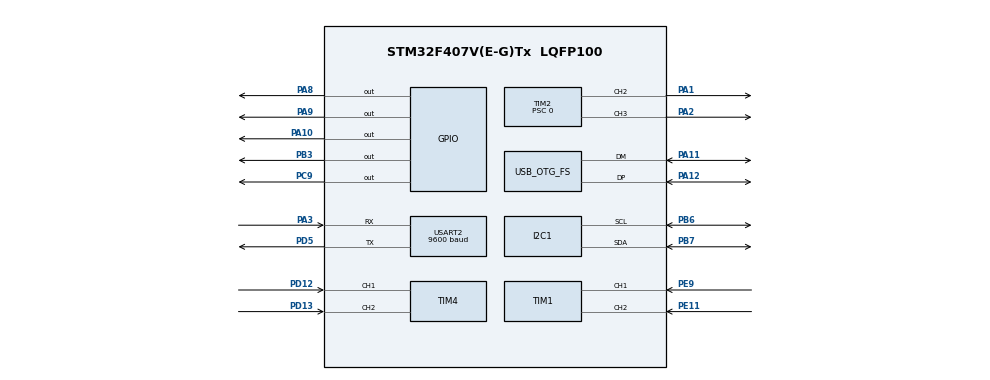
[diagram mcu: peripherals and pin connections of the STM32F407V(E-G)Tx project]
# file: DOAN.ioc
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I2C1.I2C_Mode=I2C_Fast
Mcu.Family=STM32F4
Mcu.Name=STM32F407V(E-G)Tx
Mcu.Package=LQFP100
NVIC.OTG_FS_IRQn=true\:5\:0\:true\:false\:true\:false\:true\:true
NVIC.PriorityGroup=NVIC_PRIORITYGROUP_4
NVIC.TIM3_IRQn=true\:0\:0\:true\:false\:true\:true\:true\:true
NVIC.USART2_IRQn=true\:0\:0\:false\:false\:true\:true\:true\:true
PA1.Signal=S_TIM2_CH2
PA10.Signal=GPIO_Output
PA11.Mode=Device_Only
PA11.Signal=USB_OTG_FS_DM
PA12.Mode=Device_Only
PA12.Signal=USB_OTG_FS_DP
PA13.Mode=Serial_Wire
PA13.Signal=SYS_JTMS-SWDIO
PA14.Mode=Serial_Wire
PA14.Signal=SYS_JTCK-SWCLK
PA2.Signal=S_TIM2_CH3
PA3.Mode=Asynchronous
PA3.Signal=USART2_RX
PA8.Signal=GPIO_Output
PA9.Signal=GPIO_Output
PB3.Signal=GPIO_Output
PB6.Mode=I2C
PB6.Signal=I2C1_SCL
PB7.Mode=I2C
PB7.Signal=I2C1_SDA
PC9.Signal=GPIO_Output
PD12.GPIO_PuPd=GPIO_PULLUP
PD12.Signal=S_TIM4_CH1
PD13.GPIO_PuPd=GPIO_PULLUP
PD13.Signal=S_TIM4_CH2
PD5.Mode=Asynchronous
PD5.Signal=USART2_TX
PE11.GPIO_PuPd=GPIO_PULLUP
PE11.Signal=S_TIM1_CH2
PE9.GPIO_PuPd=GPIO_PULLUP
PE9.Signal=S_TIM1_CH1
PH0-OSC_IN.Mode=HSE-External-Oscillator
PH0-OSC_IN.Signal=RCC_OSC_IN
PH1-OSC_OUT.Mode=HSE-External-Oscillator
PH1-OSC_OUT.Signal=RCC_OSC_OUT
ProjectManager.HeapSize=0x200
ProjectManager.StackSize=0x400
ProjectManager.TargetToolchain=STM32CubeIDE
RCC.48MHZClocksFreq_Value=48000000
RCC.AHBFreq_Value=168000000
RCC.APB1CLKDivider=RCC_HCLK_DIV4
RCC.APB1Freq_Value=42000000
RCC.APB1TimFreq_Value=84000000
RCC.APB2CLKDivider=RCC_HCLK_DIV4
RCC.APB2Freq_Value=42000000
RCC.APB2TimFreq_Value=84000000
RCC.CortexFreq_Value=168000000
RCC.HCLKFreq_Value=168000000
RCC.HSE_VALUE=25000000
RCC.HSI_VALUE=16000000
RCC.LSE_VALUE=32768
RCC.PLLM=25
RCC.PLLN=336
RCC.PLLQ=7
RCC.SYSCLKFreq_VALUE=168000000
RCC.SYSCLKSource=RCC_SYSCLKSOURCE_PLLCLK
RCC.VCOOutputFreq_Value=336000000
SH.S_TIM1_CH1.0=TIM1_CH1,Encoder_Interface
SH.S_TIM1_CH2.0=TIM1_CH2,Encoder_Interface
SH.S_TIM2_CH2.0=TIM2_CH2,PWM Generation2 CH2
SH.S_TIM2_CH3.0=TIM2_CH3,PWM Generation3 CH3
SH.S_TIM4_CH1.0=TIM4_CH1,Encoder_Interface
SH.S_TIM4_CH2.0=TIM4_CH2,Encoder_Interface
TIM1.EncoderMode=TIM_ENCODERMODE_TI12
TIM1.IC1Polarity=TIM_ICPOLARITY_FALLING
TIM1.IC2Filter=0
TIM1.IC2Polarity=TIM_ICPOLARITY_FALLING
TIM2.AutoReloadPreload=TIM_AUTORELOAD_PRELOAD_ENABLE
TIM2.Channel-PWM\ Generation2\ CH2=TIM_CHANNEL_2
TIM2.Channel-PWM\ Generation3\ CH3=TIM_CHANNEL_3
TIM2.Period=4199
TIM2.Prescaler=0
TIM3.AutoReloadPreload=TIM_AUTORELOAD_PRELOAD_ENABLE
TIM3.Period=99
TIM3.Prescaler=8399
TIM4.EncoderMode=TIM_ENCODERMODE_TI12
TIM4.IC1Polarity=TIM_ICPOLARITY_FALLING
TIM4.IC2Filter=0
TIM4.IC2Polarity=TIM_ICPOLARITY_FALLING
USART2.BaudRate=9600
USART2.VirtualMode=VM_ASYNC
USB_DEVICE.CLASS_NAME_FS=CDC
USB_DEVICE.VirtualMode-CDC_FS=Cdc
USB_DEVICE.VirtualModeFS=Cdc_FS
USB_OTG_FS.VirtualMode=Device_Only
VP_TIM2_VS_ClockSourceINT.Mode=Internal
VP_TIM3_VS_ClockSourceINT.Mode=Internal
VP_USB_DEVICE_VS_USB_DEVICE_CDC_FS.Mode=CDC_FS
board=custom

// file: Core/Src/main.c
/* USER CODE BEGIN Header */
/**
  ******************************************************************************
  * @file           : main.c
  * @brief          : Main program body - Robot Balancing (Single Loop)
  ******************************************************************************
  */
/* USER CODE END Header */
#include "main.h"
#include "usb_device.h"

/* USER CODE BEGIN Includes */
#include <stdio.h>
#include <stdlib.h>
#include <math.h>
#include "string.h"
#include "usbd_cdc_if.h"
#include "mpu6050.h"
#include "pid.h"
#include "PID_motor.h"
#include "state_machine.h"
/* USER CODE END Includes */

/* USER CODE BEGIN PTD */
typedef enum {
    ROBOT_OFF,
    ROBOT_RUNNING
} RobotState_t;
/* USER CODE END PTD */

I2C_HandleTypeDef hi2c1;

TIM_HandleTypeDef htim1;
TIM_HandleTypeDef htim2;
TIM_HandleTypeDef htim3;
TIM_HandleTypeDef htim4;

UART_HandleTypeDef huart2;

/* USER CODE BEGIN PV */

gyro_data gyro;
accel_data accel;
filtered_angle_t angle = {0, 0};

volatile float Angle_Pitch = 0.0f;
volatile float Angle_Roll = 0.0f;
volatile float Gyro_X_Rate = 0.0f;
volatile float Gyro_Y_Rate = 0.0f;

//float Kp_ang = 60.0f;
//float Ki_ang = 0.015f;
//float Kd_ang = 1.45f;

float Kp_ang = 60.0f;
float Ki_ang = 0.005f;
float Kd_ang = 1.2;

float Kp_spd = 5.0f;
float Ki_spd = 0.005f;

float Setpoint_Angle = 8.0f;
volatile uint32_t cnt = 0;

// --- THÔNG SỐ CẤU HÌNH ---
        float Base_Angle = 8.0f;   // Góc cân bằng chuẩn (Đứng yên)
        float Tilt_Step  = 5.5f;   // Độ nghiêng để chạy tới
        float Ramp_Step  = 0.05f;  // Độ mượt chuyển đổi (tăng số này nếu muốn chuyển trạng thái nhanh hơn)

float Error_Ang = 0.0f;
float Prev_Error_Ang = 0.0f;
float I_Part_Ang = 0.0f;
float Target_Speed = 0.0f;

float v_filter = 0.0f;
float Encoder_Speed = 0.0f;
float Error_Spd = 0.0f;
float I_Part_Spd = 0.0f;
float PWM_Out = 0.0f;

volatile uint8_t timer_flag = 0;
const float dt = 0.01f;

int flag1, flag2, flag3 = 0;

uint8_t TxBuffer1[] = "I2C done!\r\n";
uint8_t TxBufferLen1 = sizeof(TxBuffer1);

uint8_t TxBuffer2[] = "Encoder done!\r\n";
uint8_t TxBufferLen2 = sizeof(TxBuffer2);

uint8_t TxBuffer3[] = "PWM done!\r\n";
uint8_t TxBufferLen3 = sizeof(TxBuffer3);
//char usb_buffer[64];

 int16_t enc1_new = 0;
 int16_t enc2_new = 0;
int16_t enc1_old = 0;
int16_t enc2_old = 0;

volatile uint8_t send_usb_flag = 0;
static uint16_t time_counter = 0;

//Gửi bluetooth
uint8_t rxData;

/* USER CODE END PV */

void SystemClock_Config(void);
static void MX_GPIO_Init(void);
static void MX_I2C1_Init(void);
static void MX_TIM2_Init(void);
static void MX_TIM3_Init(void);
static void MX_TIM1_Init(void);
static void MX_TIM4_Init(void);
static void MX_USART2_UART_Init(void);

/* USER CODE BEGIN 0 */
// Các biến hỗ trợ đọc encoder trong ngắt
//volatile uint8_t A_state = 0, B_state = 0;
//volatile uint8_t A2_state = 0, B2_state = 0;

/*
void HAL_GPIO_EXTI_Callback(uint16_t GPIO_Pin)
{
    if (GPIO_Pin == GPIO_PIN_0) // Encoder 1
    {
        A_state = HAL_GPIO_ReadPin(GPIOC, GPIO_PIN_0);
        B_state = HAL_GPIO_ReadPin(GPIOB, GPIO_PIN_0);
        if (A_state != B_state) encoder_value--;
        else encoder_value++;
    }
    else if (GPIO_Pin == GPIO_PIN_1) // Encoder 2
    {
        A2_state = HAL_GPIO_ReadPin(GPIOC, GPIO_PIN_1);
        B2_state = HAL_GPIO_ReadPin(GPIOB, GPIO_PIN_1);
        if (A2_state != B2_state) encoder2_value--;
        else encoder2_value++;
    }
}
*/

/* ===============================================================
 * HÀM ĐIỀU KHIỂN MOTOR
 * =============================================================== */
void Motor_Control(float pwm_input)
{
    if (pwm_input > 4199.0f) pwm_input = 4199.0f;
    else if (pwm_input < -4199.0f) pwm_input = -4199.0f;

    int pwm_val = (int)fabs(pwm_input);

    if (pwm_input > 0) // Forward
    {
        HAL_GPIO_WritePin(GPIOA, GPIO_PIN_10, 1);
        HAL_GPIO_WritePin(GPIOA, GPIO_PIN_9, 0);

        HAL_GPIO_WritePin(GPIOA, GPIO_PIN_8, 1);
        HAL_GPIO_WritePin(GPIOC, GPIO_PIN_9, 0);
    }
    else if (pwm_input < 0) // Backward
    {
        HAL_GPIO_WritePin(GPIOA, GPIO_PIN_10, 0); //AIN2
        HAL_GPIO_WritePin(GPIOA, GPIO_PIN_9, 1); //AIN1

        HAL_GPIO_WritePin(GPIOA, GPIO_PIN_8, 0); //BIN1
        HAL_GPIO_WritePin(GPIOC, GPIO_PIN_9, 1); //BIN2
    }
    else // Stop
    {
        pwm_val = 0;
    }

    __HAL_TIM_SET_COMPARE(&htim2, TIM_CHANNEL_2, pwm_val);
    __HAL_TIM_SET_COMPARE(&htim2, TIM_CHANNEL_3, pwm_val);
}

/*
#define ADD 0xD0
#define RTD 57.2957

int16_t ax = 0, ay = 0, az = 0, gx = 0, gy = 0, gz = 0;
float AX, AY, AZ, GX, GY, GZ;
float pitch = 0, roll = 0, prev_pitch = 0;
float filtered_pitch = 0;

void MPU6050Init(void)
{
	uint8_t check;
	uint8_t mData;
	HAL_I2C_Mem_Read(&hi2c1, ADD, 0x75, 1, &check, 1, 1000);
	if(check == 0x68)
	{
		mData = 0x00;
		HAL_I2C_Mem_Write(&hi2c1, ADD, 0x6B, 1, &mData, 1, 1000);
		mData = 0x07;
		HAL_I2C_Mem_Write(&hi2c1, ADD, 0x19, 1, &mData, 1, 1000);
		mData = 0x00;
		HAL_I2C_Mem_Write(&hi2c1, ADD, 0x1B, 1, &mData, 1, 1000);
		mData = 0x00;
		HAL_I2C_Mem_Write(&hi2c1, ADD, 0x1C, 1, &mData, 1, 1000);
	}
}

void MPU6050ReadG(void)
{
	uint8_t dataG[6];
	HAL_I2C_Mem_Read(&hi2c1, ADD, 0x43, 1, dataG, 6, 1000);
	gx = (int16_t) (dataG[0] << 8 | dataG[1]);
	gy = (int16_t) (dataG[2] << 8 | dataG[3]);
	gz = (int16_t) (dataG[4] << 8 | dataG[5]);
	GX =(float) gx / 131.0;
	GY =(float) gy / 131.0;
	GZ =(float) gz / 131.0;

}

void MPU6050ReadA(void)
{
	uint8_t dataA[6];
	HAL_I2C_Mem_Read(&hi2c1, ADD, 0x3B, 1, dataA, 6, 1000);
	ax = (int16_t) (dataA[0] << 8 | dataA[1]);
	ay = (int16_t) (dataA[2] << 8 | dataA[3]);
	az = (int16_t) (dataA[4] << 8 | dataA[5]);
	AX = (float) ax / 16384.0;
	AY = (float) ay / 16384.0;
	AZ = (float) az / 16384.0;

}

void MPU6050_getAngle(float AX, float AY, float AZ, float GX, float GY, float GZ)
{
	float pitchG = pitch + GX * (10000 / 1000000.0f);
	float rollG = roll + GY * (10000 / 1000000.0f);

	float pitchA = atan2(AY, sqrt(AX * AX + AZ * AZ)) * RTD;
	float rollA = atan2(AX, sqrt(AY * AY + AZ * AZ)) * RTD;

	pitch = 0.98 * pitchG + 0.02 * pitchA;
	roll = 0.98 * rollG + 0.02 * rollA;
}

void MPU6050_filter(float pitch, float GX, float dt)
{
	filtered_pitch = 0.98f * (prev_pitch + GX * dt) + 0.02 * pitch;
	prev_pitch = filtered_pitch;
}
*/

/* USER CODE END 0 */

int main(void)
{

  /* MCU Configuration--------------------------------------------------------*/

  /* Reset of all peripherals, Initializes the Flash interface and the Systick. */
  HAL_Init();

  /* Configure the system clock */
  SystemClock_Config();

  /* Initialize all configured peripherals */
  MX_GPIO_Init();
  MX_I2C1_Init();
  MX_TIM2_Init();
  MX_TIM3_Init();
  MX_USB_DEVICE_Init();
  MX_TIM1_Init();
  MX_TIM4_Init();
  MX_USART2_UART_Init();
  /* USER CODE BEGIN 2 */
  HAL_NVIC_SetPriority(SysTick_IRQn, 0, 0);
  //HAL_NVIC_SetPriority(OTG_FS_IRQn, 5, 0);7-
  mpu6050_init();
  //MPU6050Init();

  // 3. Enable Motor Driver
  HAL_GPIO_WritePin(GPIOB, GPIO_PIN_3, GPIO_PIN_SET);

  // 4. Start Timer
  HAL_TIM_Base_Start_IT(&htim3);
  HAL_TIM_PWM_Start(&htim2, TIM_CHANNEL_2);
  HAL_TIM_PWM_Start(&htim2, TIM_CHANNEL_3);

  HAL_TIM_Encoder_Start(&htim1, TIM_CHANNEL_ALL);
  HAL_TIM_Encoder_Start(&htim4, TIM_CHANNEL_ALL);

  //HAL_UART_Receive_IT(&huart2,&rxData,1);
  /* USER CODE END 2 */

  /* Infinite loop */
  /* USER CODE BEGIN WHILE */
  while (1)
  {
	  /*
	  if(send_usb_flag == 1)
	  {
		  send_usb_flag = 0;
		  int len = sprintf(usb_buffer, "%.2f,%.2f,%.2f\r\n", Angle_Pitch, 1000.0f, v_filter);
		  int len = sprintf(usb_buffer, "%d,%d,%.0f,%.0f,%.0f\r\n", enc1_new, enc2_new, Angle_Pitch, PWM_Out, Encoder_Speed);
		  CDC_Transmit_FS((uint8_t*)usb_buffer, len);
	  }
	  */

    /* USER CODE END WHILE */

  }
}

void SystemClock_Config(void)
{
  RCC_OscInitTypeDef RCC_OscInitStruct = {0};
  RCC_ClkInitTypeDef RCC_ClkInitStruct = {0};

  /** Configure the main internal regulator output voltage
  */
  __HAL_RCC_PWR_CLK_ENABLE();
  __HAL_PWR_VOLTAGESCALING_CONFIG(PWR_REGULATOR_VOLTAGE_SCALE1);

  /** Initializes the RCC Oscillators according to the specified parameters
  * in the RCC_OscInitTypeDef structure.
  */
  RCC_OscInitStruct.OscillatorType = RCC_OSCILLATORTYPE_HSE;
  RCC_OscInitStruct.HSEState = RCC_HSE_ON;
  RCC_OscInitStruct.PLL.PLLState = RCC_PLL_ON;
  RCC_OscInitStruct.PLL.PLLSource = RCC_PLLSOURCE_HSE;
  RCC_OscInitStruct.PLL.PLLM = 8;
  RCC_OscInitStruct.PLL.PLLN = 336;
  RCC_OscInitStruct.PLL.PLLP = RCC_PLLP_DIV2;
  RCC_OscInitStruct.PLL.PLLQ = 7;
  if (HAL_RCC_OscConfig(&RCC_OscInitStruct) != HAL_OK)
  {
    Error_Handler();
  }

  /** Initializes the CPU, AHB and APB buses clocks
  */
  RCC_ClkInitStruct.ClockType = RCC_CLOCKTYPE_HCLK|RCC_CLOCKTYPE_SYSCLK
                              |RCC_CLOCKTYPE_PCLK1|RCC_CLOCKTYPE_PCLK2;
  RCC_ClkInitStruct.SYSCLKSource = RCC_SYSCLKSOURCE_PLLCLK;
  RCC_ClkInitStruct.AHBCLKDivider = RCC_SYSCLK_DIV1;
  RCC_ClkInitStruct.APB1CLKDivider = RCC_HCLK_DIV4;
  RCC_ClkInitStruct.APB2CLKDivider = RCC_HCLK_DIV4;

  if (HAL_RCC_ClockConfig(&RCC_ClkInitStruct, FLASH_LATENCY_5) != HAL_OK)
  {
    Error_Handler();
  }
}

static void MX_I2C1_Init(void)
{

  hi2c1.Instance = I2C1;
  hi2c1.Init.ClockSpeed = 400000;
  hi2c1.Init.DutyCycle = I2C_DUTYCYCLE_2;
  hi2c1.Init.OwnAddress1 = 0;
  hi2c1.Init.AddressingMode = I2C_ADDRESSINGMODE_7BIT;
  hi2c1.Init.DualAddressMode = I2C_DUALADDRESS_DISABLE;
  hi2c1.Init.OwnAddress2 = 0;
  hi2c1.Init.GeneralCallMode = I2C_GENERALCALL_DISABLE;
  hi2c1.Init.NoStretchMode = I2C_NOSTRETCH_DISABLE;
  if (HAL_I2C_Init(&hi2c1) != HAL_OK)
  {
    Error_Handler();
  }

}

static void MX_TIM1_Init(void)
{

  TIM_Encoder_InitTypeDef sConfig = {0};
  TIM_MasterConfigTypeDef sMasterConfig = {0};

  htim1.Instance = TIM1;
  htim1.Init.Prescaler = 0;
  htim1.Init.CounterMode = TIM_COUNTERMODE_UP;
  htim1.Init.Period = 65535;
  htim1.Init.ClockDivision = TIM_CLOCKDIVISION_DIV1;
  htim1.Init.RepetitionCounter = 0;
  htim1.Init.AutoReloadPreload = TIM_AUTORELOAD_PRELOAD_DISABLE;
  sConfig.EncoderMode = TIM_ENCODERMODE_TI12;
  sConfig.IC1Polarity = TIM_ICPOLARITY_FALLING;
  sConfig.IC1Selection = TIM_ICSELECTION_DIRECTTI;
  sConfig.IC1Prescaler = TIM_ICPSC_DIV1;
  sConfig.IC1Filter = 0;
  sConfig.IC2Polarity = TIM_ICPOLARITY_FALLING;
  sConfig.IC2Selection = TIM_ICSELECTION_DIRECTTI;
  sConfig.IC2Prescaler = TIM_ICPSC_DIV1;
  sConfig.IC2Filter = 0;
  if (HAL_TIM_Encoder_Init(&htim1, &sConfig) != HAL_OK)
  {
    Error_Handler();
  }
  sMasterConfig.MasterOutputTrigger = TIM_TRGO_RESET;
  sMasterConfig.MasterSlaveMode = TIM_MASTERSLAVEMODE_DISABLE;
  if (HAL_TIMEx_MasterConfigSynchronization(&htim1, &sMasterConfig) != HAL_OK)
  {
    Error_Handler();
  }

}

static void MX_TIM2_Init(void)
{

  TIM_ClockConfigTypeDef sClockSourceConfig = {0};
  TIM_MasterConfigTypeDef sMasterConfig = {0};
  TIM_OC_InitTypeDef sConfigOC = {0};

  htim2.Instance = TIM2;
  htim2.Init.Prescaler = 0;
  htim2.Init.CounterMode = TIM_COUNTERMODE_UP;
  htim2.Init.Period = 4199;
  htim2.Init.ClockDivision = TIM_CLOCKDIVISION_DIV1;
  htim2.Init.AutoReloadPreload = TIM_AUTORELOAD_PRELOAD_ENABLE;
  if (HAL_TIM_Base_Init(&htim2) != HAL_OK)
  {
    Error_Handler();
  }
  sClockSourceConfig.ClockSource = TIM_CLOCKSOURCE_INTERNAL;
  if (HAL_TIM_ConfigClockSource(&htim2, &sClockSourceConfig) != HAL_OK)
  {
    Error_Handler();
  }
  if (HAL_TIM_PWM_Init(&htim2) != HAL_OK)
  {
    Error_Handler();
  }
  sMasterConfig.MasterOutputTrigger = TIM_TRGO_RESET;
  sMasterConfig.MasterSlaveMode = TIM_MASTERSLAVEMODE_DISABLE;
  if (HAL_TIMEx_MasterConfigSynchronization(&htim2, &sMasterConfig) != HAL_OK)
  {
    Error_Handler();
  }
  sConfigOC.OCMode = TIM_OCMODE_PWM1;
  sConfigOC.Pulse = 0;
  sConfigOC.OCPolarity = TIM_OCPOLARITY_HIGH;
  sConfigOC.OCFastMode = TIM_OCFAST_DISABLE;
  if (HAL_TIM_PWM_ConfigChannel(&htim2, &sConfigOC, TIM_CHANNEL_2) != HAL_OK)
  {
    Error_Handler();
  }
  if (HAL_TIM_PWM_ConfigChannel(&htim2, &sConfigOC, TIM_CHANNEL_3) != HAL_OK)
  {
    Error_Handler();
  }
  HAL_TIM_MspPostInit(&htim2);

}

static void MX_TIM3_Init(void)
{

  TIM_ClockConfigTypeDef sClockSourceConfig = {0};
  TIM_MasterConfigTypeDef sMasterConfig = {0};

  htim3.Instance = TIM3;
  htim3.Init.Prescaler = 8399;
  htim3.Init.CounterMode = TIM_COUNTERMODE_UP;
  htim3.Init.Period = 99;
  htim3.Init.ClockDivision = TIM_CLOCKDIVISION_DIV1;
  htim3.Init.AutoReloadPreload = TIM_AUTORELOAD_PRELOAD_ENABLE;
  if (HAL_TIM_Base_Init(&htim3) != HAL_OK)
  {
    Error_Handler();
  }
  sClockSourceConfig.ClockSource = TIM_CLOCKSOURCE_INTERNAL;
  if (HAL_TIM_ConfigClockSource(&htim3, &sClockSourceConfig) != HAL_OK)
  {
    Error_Handler();
  }
  sMasterConfig.MasterOutputTrigger = TIM_TRGO_RESET;
  sMasterConfig.MasterSlaveMode = TIM_MASTERSLAVEMODE_DISABLE;
  if (HAL_TIMEx_MasterConfigSynchronization(&htim3, &sMasterConfig) != HAL_OK)
  {
    Error_Handler();
  }
  /* USER CODE BEGIN TIM3_Init 2 */
  //HAL_NVIC_SetPriority(TIM3_IRQn, 1, 0);
  //HAL_NVIC_EnableIRQ(TIM3_IRQn);

  /* USER CODE END TIM3_Init 2 */

}

static void MX_TIM4_Init(void)
{

  TIM_Encoder_InitTypeDef sConfig = {0};
  TIM_MasterConfigTypeDef sMasterConfig = {0};

  htim4.Instance = TIM4;
  htim4.Init.Prescaler = 0;
  htim4.Init.CounterMode = TIM_COUNTERMODE_UP;
  htim4.Init.Period = 65535;
  htim4.Init.ClockDivision = TIM_CLOCKDIVISION_DIV1;
  htim4.Init.AutoReloadPreload = TIM_AUTORELOAD_PRELOAD_DISABLE;
  sConfig.EncoderMode = TIM_ENCODERMODE_TI12;
  sConfig.IC1Polarity = TIM_ICPOLARITY_FALLING;
  sConfig.IC1Selection = TIM_ICSELECTION_DIRECTTI;
  sConfig.IC1Prescaler = TIM_ICPSC_DIV1;
  sConfig.IC1Filter = 0;
  sConfig.IC2Polarity = TIM_ICPOLARITY_FALLING;
  sConfig.IC2Selection = TIM_ICSELECTION_DIRECTTI;
  sConfig.IC2Prescaler = TIM_ICPSC_DIV1;
  sConfig.IC2Filter = 0;
  if (HAL_TIM_Encoder_Init(&htim4, &sConfig) != HAL_OK)
  {
    Error_Handler();
  }
  sMasterConfig.MasterOutputTrigger = TIM_TRGO_RESET;
  sMasterConfig.MasterSlaveMode = TIM_MASTERSLAVEMODE_DISABLE;
  if (HAL_TIMEx_MasterConfigSynchronization(&htim4, &sMasterConfig) != HAL_OK)
  {
    Error_Handler();
  }

}

static void MX_USART2_UART_Init(void)
{

  huart2.Instance = USART2;
  huart2.Init.BaudRate = 9600;
  huart2.Init.WordLength = UART_WORDLENGTH_8B;
  huart2.Init.StopBits = UART_STOPBITS_1;
  huart2.Init.Parity = UART_PARITY_NONE;
  huart2.Init.Mode = UART_MODE_TX_RX;
  huart2.Init.HwFlowCtl = UART_HWCONTROL_NONE;
  huart2.Init.OverSampling = UART_OVERSAMPLING_16;
  if (HAL_UART_Init(&huart2) != HAL_OK)
  {
    Error_Handler();
  }

}

static void MX_GPIO_Init(void)
{
  GPIO_InitTypeDef GPIO_InitStruct = {0};

  /* GPIO Ports Clock Enable */
  __HAL_RCC_GPIOH_CLK_ENABLE();
  __HAL_RCC_GPIOA_CLK_ENABLE();
  __HAL_RCC_GPIOE_CLK_ENABLE();
  __HAL_RCC_GPIOD_CLK_ENABLE();
  __HAL_RCC_GPIOC_CLK_ENABLE();
  __HAL_RCC_GPIOB_CLK_ENABLE();

  /*Configure GPIO pin Output Level */
  HAL_GPIO_WritePin(GPIOC, GPIO_PIN_9, GPIO_PIN_RESET);

  /*Configure GPIO pin Output Level */
  HAL_GPIO_WritePin(GPIOA, GPIO_PIN_8|GPIO_PIN_9|GPIO_PIN_10, GPIO_PIN_RESET);

  /*Configure GPIO pin Output Level */
  HAL_GPIO_WritePin(GPIOB, GPIO_PIN_3, GPIO_PIN_RESET);

  /*Configure GPIO pin : PC9 */
  GPIO_InitStruct.Pin = GPIO_PIN_9;
  GPIO_InitStruct.Mode = GPIO_MODE_OUTPUT_PP;
  GPIO_InitStruct.Pull = GPIO_NOPULL;
  GPIO_InitStruct.Speed = GPIO_SPEED_FREQ_LOW;
  HAL_GPIO_Init(GPIOC, &GPIO_InitStruct);

  /*Configure GPIO pins : PA8 PA9 PA10 */
  GPIO_InitStruct.Pin = GPIO_PIN_8|GPIO_PIN_9|GPIO_PIN_10;
  GPIO_InitStruct.Mode = GPIO_MODE_OUTPUT_PP;
  GPIO_InitStruct.Pull = GPIO_NOPULL;
  GPIO_InitStruct.Speed = GPIO_SPEED_FREQ_LOW;
  HAL_GPIO_Init(GPIOA, &GPIO_InitStruct);

  /*Configure GPIO pin : PB3 */
  GPIO_InitStruct.Pin = GPIO_PIN_3;
  GPIO_InitStruct.Mode = GPIO_MODE_OUTPUT_PP;
  GPIO_InitStruct.Pull = GPIO_NOPULL;
  GPIO_InitStruct.Speed = GPIO_SPEED_FREQ_LOW;
  HAL_GPIO_Init(GPIOB, &GPIO_InitStruct);

  /* USER CODE BEGIN MX_GPIO_Init_2 */
  /* EXTI Interrupt Init */
  //HAL_NVIC_SetPriority(EXTI0_IRQn, 1, 0);
  //HAL_NVIC_EnableIRQ(EXTI0_IRQn);

  //HAL_NVIC_SetPriority(EXTI1_IRQn, 1, 0);
  //HAL_NVIC_EnableIRQ(EXTI1_IRQn);

  /* USER CODE END MX_GPIO_Init_2 */
}

/* USER CODE BEGIN 4 */
/* USER CODE BEGIN 4 */
/* USER CODE BEGIN 4 */
void HAL_TIM_PeriodElapsedCallback(TIM_HandleTypeDef *htim)
{
    if (htim->Instance == TIM3)
    {
        mpu6050_read_all(&accel, &gyro);
        mpu6050_complementary_filter(&gyro, &accel, &angle, dt);
        Angle_Pitch = angle.pitch;

        enc1_new = (int16_t)__HAL_TIM_GET_COUNTER(&htim4);
        enc2_new = (int16_t)__HAL_TIM_GET_COUNTER(&htim1);
        int16_t delta1 = enc1_new - enc1_old;
        int16_t delta2 = enc2_new - enc2_old;
        enc1_old = enc1_new;
        enc2_old = enc2_new;

        Encoder_Speed = ((float)delta1 + (float)delta2) / 2.0f / dt;
        cnt++;

        float Desired_Angle = Base_Angle;
        static float Smooth_Setpoint = 8.0f;

        if (cnt < 400)
        {
            Desired_Angle = Base_Angle + Tilt_Step;
        }
        else
        {
            Desired_Angle = Base_Angle;
        }

        if (Smooth_Setpoint < Desired_Angle)
        {
            Smooth_Setpoint += Ramp_Step;
            if (Smooth_Setpoint > Desired_Angle) Smooth_Setpoint = Desired_Angle;
        }
        else if (Smooth_Setpoint > Desired_Angle)
        {
            Smooth_Setpoint -= Ramp_Step;
            if (Smooth_Setpoint < Desired_Angle) Smooth_Setpoint = Desired_Angle;
        }
        Setpoint_Angle = Smooth_Setpoint;

        Error_Ang = Setpoint_Angle - Angle_Pitch;
        float P_Ang = Kp_ang * Error_Ang;

        I_Part_Ang += (Ki_ang * Error_Ang * dt);
        if (I_Part_Ang > 350) I_Part_Ang = 350;
        else if (I_Part_Ang < -350) I_Part_Ang = -350;

        float D_Ang = Kd_ang * (Error_Ang - Prev_Error_Ang) / dt;
        Prev_Error_Ang = Error_Ang;

        Target_Speed = P_Ang + I_Part_Ang + D_Ang;

        // Giới hạn Target Speed
        if (Target_Speed > 7000) Target_Speed = 7000;
        else if (Target_Speed < -7000) Target_Speed = -7000;

        Kp_spd = 5.0f;
        Ki_spd = 0.005f;

        Error_Spd = Target_Speed - Encoder_Speed;

        float P_Spd = Kp_spd * Error_Spd;

        I_Part_Spd += (Ki_spd * Error_Spd * dt);
        if (I_Part_Spd > 4000) I_Part_Spd = 4000;
        else if (I_Part_Spd < -4000) I_Part_Spd = -4000;

        PWM_Out = P_Spd + I_Part_Spd;

        // Bù Deadzone
        if (PWM_Out > 0) PWM_Out += 250;
        else if (PWM_Out < 0) PWM_Out -= 150;

        Motor_Control(PWM_Out);
    }
}
/* USER CODE END 4 */
/* USER CODE END 4 */

/*
void HAL_UART_RxCpltCallback(UART_HandleTypeDef *huart)
{
  if(huart->Instance==USART2)
  {
    if(rxData==78) // Ascii value of 'N' is 78 (N for NO)
    {
    	Setpoint_Angle = 8.0f;
    }
    else if (rxData==89) // Ascii value of 'Y' is 89 (Y for YES)
    {
    	Setpoint_Angle = 12.0f;
    }
    HAL_UART_Receive_IT(&huart2,&rxData,1); // Enabling interrupt receive again
  }
}
*/
/* USER CODE END 4 */

void Error_Handler(void)
{
  __disable_irq();
  while (1)
  {
  }
}
